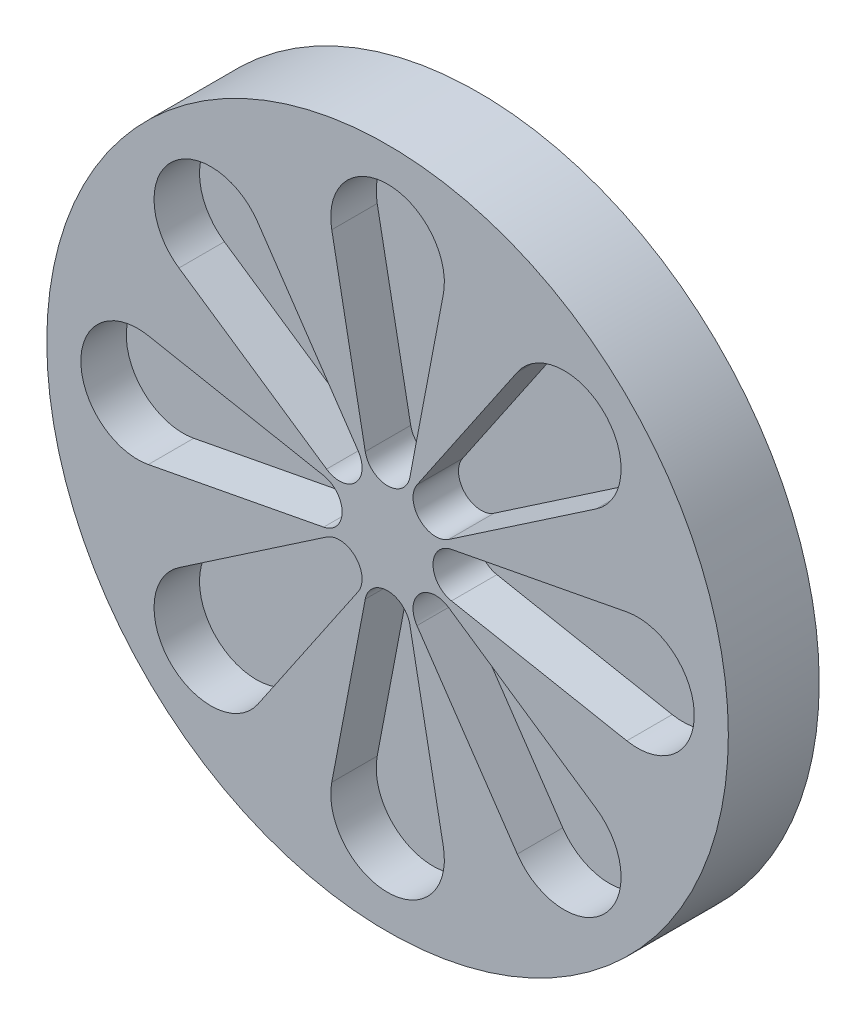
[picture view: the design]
ISO-10303-21;
HEADER;
FILE_DESCRIPTION(('STEP AP214'),'2;1');
FILE_NAME('part.step','',(''),(''),'','','');
FILE_SCHEMA(('AUTOMOTIVE_DESIGN { 1 0 10303 214 1 1 1 1 }'));
ENDSEC;
DATA;
#1=APPLICATION_CONTEXT('core data for automotive mechanical design processes');
#2=APPLICATION_PROTOCOL_DEFINITION('international standard','automotive_design',2000,#1);
#3=PRODUCT_CONTEXT('',#1,'mechanical');
#4=PRODUCT('Part','Part','',(#3));
#5=PRODUCT_RELATED_PRODUCT_CATEGORY('part','',(#4));
#6=PRODUCT_DEFINITION_FORMATION('','',#4);
#7=PRODUCT_DEFINITION_CONTEXT('part definition',#1,'design');
#8=PRODUCT_DEFINITION('design','',#6,#7);
#9=PRODUCT_DEFINITION_SHAPE('','',#8);
#10=(LENGTH_UNIT() NAMED_UNIT(*) SI_UNIT(.MILLI.,.METRE.));
#11=(NAMED_UNIT(*) PLANE_ANGLE_UNIT() SI_UNIT($,.RADIAN.));
#12=(NAMED_UNIT(*) SI_UNIT($,.STERADIAN.) SOLID_ANGLE_UNIT());
#13=UNCERTAINTY_MEASURE_WITH_UNIT(LENGTH_MEASURE(1.E-05),#10,'distance_accuracy_value','');
#14=(GEOMETRIC_REPRESENTATION_CONTEXT(3) GLOBAL_UNCERTAINTY_ASSIGNED_CONTEXT((#13)) GLOBAL_UNIT_ASSIGNED_CONTEXT((#10,
#11,#12)) REPRESENTATION_CONTEXT('',''));
#15=CARTESIAN_POINT('',(0.,0.,0.));
#16=DIRECTION('',(0.,0.,1.));
#17=DIRECTION('',(1.,0.,0.));
#18=AXIS2_PLACEMENT_3D('',#15,#16,#17);
#19=CARTESIAN_POINT('',(0.,0.,40.));
#20=DIRECTION('',(0.,0.,-1.));
#21=DIRECTION('',(-1.,0.,0.));
#22=AXIS2_PLACEMENT_3D('',#19,#20,#21);
#23=CYLINDRICAL_SURFACE('',#22,150.);
#24=CARTESIAN_POINT('',(0.,0.,40.));
#25=DIRECTION('',(0.,0.,1.));
#26=DIRECTION('',(1.,0.,0.));
#27=AXIS2_PLACEMENT_3D('',#24,#25,#26);
#28=CIRCLE('',#27,150.);
#29=CARTESIAN_POINT('',(150.,0.,40.));
#30=VERTEX_POINT('',#29);
#31=EDGE_CURVE('E11',#30,#30,#28,.T.);
#32=ORIENTED_EDGE('',*,*,#31,.F.);
#33=EDGE_LOOP('',(#32));
#34=FACE_BOUND('',#33,.T.);
#35=CARTESIAN_POINT('',(0.,0.,0.));
#36=DIRECTION('',(0.,0.,1.));
#37=DIRECTION('',(1.,0.,0.));
#38=AXIS2_PLACEMENT_3D('',#35,#36,#37);
#39=CIRCLE('',#38,150.);
#40=CARTESIAN_POINT('',(150.,0.,0.));
#41=VERTEX_POINT('',#40);
#42=EDGE_CURVE('E358',#41,#41,#39,.T.);
#43=ORIENTED_EDGE('',*,*,#42,.T.);
#44=EDGE_LOOP('',(#43));
#45=FACE_BOUND('',#44,.T.);
#46=ADVANCED_FACE('F351',(#34,#45),#23,.T.);
#47=CARTESIAN_POINT('',(0.,0.,40.));
#48=DIRECTION('',(0.,0.,1.));
#49=DIRECTION('',(1.,0.,0.));
#50=AXIS2_PLACEMENT_3D('',#47,#48,#49);
#51=PLANE('',#50);
#52=CARTESIAN_POINT('',(77.7817459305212,-77.7817459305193,40.));
#53=DIRECTION('',(0.,0.,1.));
#54=DIRECTION('',(0.707106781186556,-0.707106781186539,0.));
#55=AXIS2_PLACEMENT_3D('',#52,#53,#54);
#56=CIRCLE('',#55,25.);
#57=CARTESIAN_POINT('',(57.1030338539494,-91.8313319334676,40.));
#58=VERTEX_POINT('',#57);
#59=CARTESIAN_POINT('',(91.831331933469,-57.1030338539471,40.));
#60=VERTEX_POINT('',#59);
#61=EDGE_CURVE('E365',#58,#60,#56,.T.);
#62=ORIENTED_EDGE('',*,*,#61,.F.);
#63=DIRECTION('',(0.561983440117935,-0.827148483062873,0.));
#64=VECTOR('',#63,1.);
#65=CARTESIAN_POINT('',(12.941718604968,-26.8330378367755,40.));
#66=LINE('',#65,#64);
#67=CARTESIAN_POINT('',(12.941718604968,-26.8330378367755,40.));
#68=VERTEX_POINT('',#67);
#69=EDGE_CURVE('E581',#68,#58,#66,.T.);
#70=ORIENTED_EDGE('',*,*,#69,.F.);
#71=CARTESIAN_POINT('',(21.2132034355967,-21.2132034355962,40.));
#72=DIRECTION('',(0.,0.,1.));
#73=DIRECTION('',(0.707106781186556,-0.707106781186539,0.));
#74=AXIS2_PLACEMENT_3D('',#71,#72,#73);
#75=CIRCLE('',#74,10.);
#76=CARTESIAN_POINT('',(26.8330378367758,-12.9417186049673,40.));
#77=VERTEX_POINT('',#76);
#78=EDGE_CURVE('E563',#77,#68,#75,.T.);
#79=ORIENTED_EDGE('',*,*,#78,.F.);
#80=DIRECTION('',(-0.827148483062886,0.561983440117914,0.));
#81=VECTOR('',#80,1.);
#82=CARTESIAN_POINT('',(26.8330378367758,-12.9417186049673,40.));
#83=LINE('',#82,#81);
#84=EDGE_CURVE('E574',#60,#77,#83,.T.);
#85=ORIENTED_EDGE('',*,*,#84,.F.);
#86=EDGE_LOOP('',(#62,#70,#79,#85));
#87=FACE_BOUND('',#86,.T.);
#88=CARTESIAN_POINT('',(1.1521895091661E-12,-110.,40.));
#89=DIRECTION('',(0.,0.,1.));
#90=DIRECTION('',(0.,-1.,0.));
#91=AXIS2_PLACEMENT_3D('',#88,#89,#90);
#92=CIRCLE('',#91,25.);
#93=CARTESIAN_POINT('',(-24.5566150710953,-105.3125,40.));
#94=VERTEX_POINT('',#93);
#95=CARTESIAN_POINT('',(24.5566150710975,-105.3125,40.));
#96=VERTEX_POINT('',#95);
#97=EDGE_CURVE('E373',#94,#96,#92,.T.);
#98=ORIENTED_EDGE('',*,*,#97,.F.);
#99=DIRECTION('',(-0.18749999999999,-0.982264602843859,0.));
#100=VECTOR('',#99,1.);
#101=CARTESIAN_POINT('',(-9.82264602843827,-28.1250000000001,40.));
#102=LINE('',#101,#100);
#103=CARTESIAN_POINT('',(-9.82264602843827,-28.1250000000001,40.));
#104=VERTEX_POINT('',#103);
#105=EDGE_CURVE('E606',#104,#94,#102,.T.);
#106=ORIENTED_EDGE('',*,*,#105,.F.);
#107=CARTESIAN_POINT('',(3.14233502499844E-13,-30.,40.));
#108=DIRECTION('',(0.,0.,1.));
#109=DIRECTION('',(0.,-1.,0.));
#110=AXIS2_PLACEMENT_3D('',#107,#108,#109);
#111=CIRCLE('',#110,10.);
#112=CARTESIAN_POINT('',(9.82264602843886,-28.1249999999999,40.));
#113=VERTEX_POINT('',#112);
#114=EDGE_CURVE('E603',#113,#104,#111,.T.);
#115=ORIENTED_EDGE('',*,*,#114,.F.);
#116=DIRECTION('',(-0.18750000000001,0.982264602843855,0.));
#117=VECTOR('',#116,1.);
#118=CARTESIAN_POINT('',(9.82264602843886,-28.1249999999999,40.));
#119=LINE('',#118,#117);
#120=EDGE_CURVE('E600',#96,#113,#119,.T.);
#121=ORIENTED_EDGE('',*,*,#120,.F.);
#122=EDGE_LOOP('',(#98,#106,#115,#121));
#123=FACE_BOUND('',#122,.T.);
#124=CARTESIAN_POINT('',(-77.7817459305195,-77.7817459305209,40.));
#125=DIRECTION('',(0.,0.,1.));
#126=DIRECTION('',(-0.707106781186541,-0.707106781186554,0.));
#127=AXIS2_PLACEMENT_3D('',#124,#125,#126);
#128=CIRCLE('',#127,25.);
#129=CARTESIAN_POINT('',(-91.8313319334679,-57.103033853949,40.));
#130=VERTEX_POINT('',#129);
#131=CARTESIAN_POINT('',(-57.1030338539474,-91.8313319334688,40.));
#132=VERTEX_POINT('',#131);
#133=EDGE_CURVE('E624',#130,#132,#128,.T.);
#134=ORIENTED_EDGE('',*,*,#133,.F.);
#135=DIRECTION('',(-0.827148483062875,-0.561983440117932,0.));
#136=VECTOR('',#135,1.);
#137=CARTESIAN_POINT('',(-26.8330378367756,-12.9417186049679,40.));
#138=LINE('',#137,#136);
#139=CARTESIAN_POINT('',(-26.8330378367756,-12.9417186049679,40.));
#140=VERTEX_POINT('',#139);
#141=EDGE_CURVE('E637',#140,#130,#138,.T.);
#142=ORIENTED_EDGE('',*,*,#141,.F.);
#143=CARTESIAN_POINT('',(-21.2132034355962,-21.2132034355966,40.));
#144=DIRECTION('',(0.,0.,1.));
#145=DIRECTION('',(-0.707106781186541,-0.707106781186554,0.));
#146=AXIS2_PLACEMENT_3D('',#143,#144,#145);
#147=CIRCLE('',#146,10.);
#148=CARTESIAN_POINT('',(-12.9417186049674,-26.8330378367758,40.));
#149=VERTEX_POINT('',#148);
#150=EDGE_CURVE('E634',#149,#140,#147,.T.);
#151=ORIENTED_EDGE('',*,*,#150,.F.);
#152=DIRECTION('',(0.561983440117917,0.827148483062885,0.));
#153=VECTOR('',#152,1.);
#154=CARTESIAN_POINT('',(-12.9417186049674,-26.8330378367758,40.));
#155=LINE('',#154,#153);
#156=EDGE_CURVE('E631',#132,#149,#155,.T.);
#157=ORIENTED_EDGE('',*,*,#156,.F.);
#158=EDGE_LOOP('',(#134,#142,#151,#157));
#159=FACE_BOUND('',#158,.T.);
#160=CARTESIAN_POINT('',(-110.,-7.68126339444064E-13,40.));
#161=DIRECTION('',(0.,0.,1.));
#162=DIRECTION('',(-1.,0.,0.));
#163=AXIS2_PLACEMENT_3D('',#160,#161,#162);
#164=CIRCLE('',#163,25.);
#165=CARTESIAN_POINT('',(-105.3125,24.5566150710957,40.));
#166=VERTEX_POINT('',#165);
#167=CARTESIAN_POINT('',(-105.3125,-24.5566150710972,40.));
#168=VERTEX_POINT('',#167);
#169=EDGE_CURVE('E655',#166,#168,#164,.T.);
#170=ORIENTED_EDGE('',*,*,#169,.F.);
#171=DIRECTION('',(-0.982264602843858,0.187499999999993,0.));
#172=VECTOR('',#171,1.);
#173=CARTESIAN_POINT('',(-28.1250000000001,9.82264602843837,40.));
#174=LINE('',#173,#172);
#175=CARTESIAN_POINT('',(-28.1250000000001,9.82264602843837,40.));
#176=VERTEX_POINT('',#175);
#177=EDGE_CURVE('E669',#176,#166,#174,.T.);
#178=ORIENTED_EDGE('',*,*,#177,.F.);
#179=CARTESIAN_POINT('',(-30.,-2.09489001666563E-13,40.));
#180=DIRECTION('',(0.,0.,1.));
#181=DIRECTION('',(-1.,0.,0.));
#182=AXIS2_PLACEMENT_3D('',#179,#180,#181);
#183=CIRCLE('',#182,10.);
#184=CARTESIAN_POINT('',(-28.1249999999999,-9.82264602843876,40.));
#185=VERTEX_POINT('',#184);
#186=EDGE_CURVE('E666',#185,#176,#183,.T.);
#187=ORIENTED_EDGE('',*,*,#186,.F.);
#188=DIRECTION('',(0.982264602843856,0.187500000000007,0.));
#189=VECTOR('',#188,1.);
#190=CARTESIAN_POINT('',(-28.1249999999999,-9.82264602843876,40.));
#191=LINE('',#190,#189);
#192=EDGE_CURVE('E663',#168,#185,#191,.T.);
#193=ORIENTED_EDGE('',*,*,#192,.F.);
#194=EDGE_LOOP('',(#170,#178,#187,#193));
#195=FACE_BOUND('',#194,.T.);
#196=CARTESIAN_POINT('',(-77.7817459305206,77.7817459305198,40.));
#197=DIRECTION('',(0.,0.,1.));
#198=DIRECTION('',(-0.707106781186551,0.707106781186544,0.));
#199=AXIS2_PLACEMENT_3D('',#196,#197,#198);
#200=CIRCLE('',#199,25.);
#201=CARTESIAN_POINT('',(-57.1030338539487,91.831331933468,40.));
#202=VERTEX_POINT('',#201);
#203=CARTESIAN_POINT('',(-91.8313319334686,57.1030338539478,40.));
#204=VERTEX_POINT('',#203);
#205=EDGE_CURVE('E687',#202,#204,#200,.T.);
#206=ORIENTED_EDGE('',*,*,#205,.F.);
#207=DIRECTION('',(-0.561983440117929,0.827148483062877,0.));
#208=VECTOR('',#207,1.);
#209=CARTESIAN_POINT('',(-12.9417186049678,26.8330378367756,40.));
#210=LINE('',#209,#208);
#211=CARTESIAN_POINT('',(-12.9417186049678,26.8330378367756,40.));
#212=VERTEX_POINT('',#211);
#213=EDGE_CURVE('E701',#212,#202,#210,.T.);
#214=ORIENTED_EDGE('',*,*,#213,.F.);
#215=CARTESIAN_POINT('',(-21.2132034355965,21.2132034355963,40.));
#216=DIRECTION('',(0.,0.,1.));
#217=DIRECTION('',(-0.707106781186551,0.707106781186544,0.));
#218=AXIS2_PLACEMENT_3D('',#215,#216,#217);
#219=CIRCLE('',#218,10.);
#220=CARTESIAN_POINT('',(-26.8330378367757,12.9417186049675,40.));
#221=VERTEX_POINT('',#220);
#222=EDGE_CURVE('E698',#221,#212,#219,.T.);
#223=ORIENTED_EDGE('',*,*,#222,.F.);
#224=DIRECTION('',(0.827148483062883,-0.56198344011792,0.));
#225=VECTOR('',#224,1.);
#226=CARTESIAN_POINT('',(-26.8330378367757,12.9417186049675,40.));
#227=LINE('',#226,#225);
#228=EDGE_CURVE('E695',#204,#221,#227,.T.);
#229=ORIENTED_EDGE('',*,*,#228,.F.);
#230=EDGE_LOOP('',(#206,#214,#223,#229));
#231=FACE_BOUND('',#230,.T.);
#232=CARTESIAN_POINT('',(-3.84063169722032E-13,110.,40.));
#233=DIRECTION('',(0.,0.,1.));
#234=DIRECTION('',(0.,1.,0.));
#235=AXIS2_PLACEMENT_3D('',#232,#233,#234);
#236=CIRCLE('',#235,25.);
#237=CARTESIAN_POINT('',(24.556615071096,105.3125,40.));
#238=VERTEX_POINT('',#237);
#239=CARTESIAN_POINT('',(-24.5566150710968,105.3125,40.));
#240=VERTEX_POINT('',#239);
#241=EDGE_CURVE('E719',#238,#240,#236,.T.);
#242=ORIENTED_EDGE('',*,*,#241,.F.);
#243=DIRECTION('',(0.187499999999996,0.982264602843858,0.));
#244=VECTOR('',#243,1.);
#245=CARTESIAN_POINT('',(9.82264602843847,28.125,40.));
#246=LINE('',#245,#244);
#247=CARTESIAN_POINT('',(9.82264602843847,28.125,40.));
#248=VERTEX_POINT('',#247);
#249=EDGE_CURVE('E733',#248,#238,#246,.T.);
#250=ORIENTED_EDGE('',*,*,#249,.F.);
#251=CARTESIAN_POINT('',(-1.04744500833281E-13,30.,40.));
#252=DIRECTION('',(0.,0.,1.));
#253=DIRECTION('',(0.,1.,0.));
#254=AXIS2_PLACEMENT_3D('',#251,#252,#253);
#255=CIRCLE('',#254,10.);
#256=CARTESIAN_POINT('',(-9.82264602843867,28.125,40.));
#257=VERTEX_POINT('',#256);
#258=EDGE_CURVE('E730',#257,#248,#255,.T.);
#259=ORIENTED_EDGE('',*,*,#258,.F.);
#260=DIRECTION('',(0.187500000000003,-0.982264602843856,0.));
#261=VECTOR('',#260,1.);
#262=CARTESIAN_POINT('',(-9.82264602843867,28.125,40.));
#263=LINE('',#262,#261);
#264=EDGE_CURVE('E727',#240,#257,#263,.T.);
#265=ORIENTED_EDGE('',*,*,#264,.F.);
#266=EDGE_LOOP('',(#242,#250,#259,#265));
#267=FACE_BOUND('',#266,.T.);
#268=CARTESIAN_POINT('',(77.7817459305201,77.7817459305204,40.));
#269=DIRECTION('',(0.,0.,1.));
#270=DIRECTION('',(0.707106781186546,0.707106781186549,0.));
#271=AXIS2_PLACEMENT_3D('',#268,#269,#270);
#272=CIRCLE('',#271,25.);
#273=CARTESIAN_POINT('',(91.8313319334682,57.1030338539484,40.));
#274=VERTEX_POINT('',#273);
#275=CARTESIAN_POINT('',(57.1030338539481,91.8313319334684,40.));
#276=VERTEX_POINT('',#275);
#277=EDGE_CURVE('E751',#274,#276,#272,.T.);
#278=ORIENTED_EDGE('',*,*,#277,.F.);
#279=DIRECTION('',(0.827148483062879,0.561983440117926,0.));
#280=VECTOR('',#279,1.);
#281=CARTESIAN_POINT('',(26.8330378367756,12.9417186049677,40.));
#282=LINE('',#281,#280);
#283=CARTESIAN_POINT('',(26.8330378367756,12.9417186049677,40.));
#284=VERTEX_POINT('',#283);
#285=EDGE_CURVE('E765',#284,#274,#282,.T.);
#286=ORIENTED_EDGE('',*,*,#285,.F.);
#287=CARTESIAN_POINT('',(21.2132034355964,21.2132034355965,40.));
#288=DIRECTION('',(0.,0.,1.));
#289=DIRECTION('',(0.707106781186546,0.707106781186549,0.));
#290=AXIS2_PLACEMENT_3D('',#287,#288,#289);
#291=CIRCLE('',#290,10.);
#292=CARTESIAN_POINT('',(12.9417186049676,26.8330378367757,40.));
#293=VERTEX_POINT('',#292);
#294=EDGE_CURVE('E762',#293,#284,#291,.T.);
#295=ORIENTED_EDGE('',*,*,#294,.F.);
#296=DIRECTION('',(-0.561983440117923,-0.827148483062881,0.));
#297=VECTOR('',#296,1.);
#298=CARTESIAN_POINT('',(12.9417186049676,26.8330378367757,40.));
#299=LINE('',#298,#297);
#300=EDGE_CURVE('E759',#276,#293,#299,.T.);
#301=ORIENTED_EDGE('',*,*,#300,.F.);
#302=EDGE_LOOP('',(#278,#286,#295,#301));
#303=FACE_BOUND('',#302,.T.);
#304=CARTESIAN_POINT('',(110.,0.,40.));
#305=DIRECTION('',(0.,0.,1.));
#306=DIRECTION('',(1.,0.,0.));
#307=AXIS2_PLACEMENT_3D('',#304,#305,#306);
#308=CIRCLE('',#307,25.);
#309=CARTESIAN_POINT('',(105.3125,-24.5566150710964,40.));
#310=VERTEX_POINT('',#309);
#311=CARTESIAN_POINT('',(105.3125,24.5566150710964,40.));
#312=VERTEX_POINT('',#311);
#313=EDGE_CURVE('E783',#310,#312,#308,.T.);
#314=ORIENTED_EDGE('',*,*,#313,.F.);
#315=DIRECTION('',(0.982264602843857,-0.1875,0.));
#316=VECTOR('',#315,1.);
#317=CARTESIAN_POINT('',(28.125,-9.82264602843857,40.));
#318=LINE('',#317,#316);
#319=CARTESIAN_POINT('',(28.125,-9.82264602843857,40.));
#320=VERTEX_POINT('',#319);
#321=EDGE_CURVE('E797',#320,#310,#318,.T.);
#322=ORIENTED_EDGE('',*,*,#321,.F.);
#323=CARTESIAN_POINT('',(30.,0.,40.));
#324=DIRECTION('',(0.,0.,1.));
#325=DIRECTION('',(1.,0.,0.));
#326=AXIS2_PLACEMENT_3D('',#323,#324,#325);
#327=CIRCLE('',#326,10.);
#328=CARTESIAN_POINT('',(28.125,9.82264602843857,40.));
#329=VERTEX_POINT('',#328);
#330=EDGE_CURVE('E794',#329,#320,#327,.T.);
#331=ORIENTED_EDGE('',*,*,#330,.F.);
#332=DIRECTION('',(-0.982264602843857,-0.1875,0.));
#333=VECTOR('',#332,1.);
#334=CARTESIAN_POINT('',(28.125,9.82264602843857,40.));
#335=LINE('',#334,#333);
#336=EDGE_CURVE('E791',#312,#329,#335,.T.);
#337=ORIENTED_EDGE('',*,*,#336,.F.);
#338=EDGE_LOOP('',(#314,#322,#331,#337));
#339=FACE_BOUND('',#338,.T.);
#340=ORIENTED_EDGE('',*,*,#31,.T.);
#341=EDGE_LOOP('',(#340));
#342=FACE_BOUND('',#341,.T.);
#343=ADVANCED_FACE('F578',(#87,#123,#159,#195,#231,#267,#303,#339,#342),#51,.T.);
#344=CARTESIAN_POINT('',(0.,0.,0.));
#345=DIRECTION('',(0.,0.,1.));
#346=DIRECTION('',(1.,0.,0.));
#347=AXIS2_PLACEMENT_3D('',#344,#345,#346);
#348=PLANE('',#347);
#349=ORIENTED_EDGE('',*,*,#42,.F.);
#350=EDGE_LOOP('',(#349));
#351=FACE_BOUND('',#350,.T.);
#352=ADVANCED_FACE('F824',(#351),#348,.F.);
#353=CARTESIAN_POINT('',(110.,0.,20.));
#354=DIRECTION('',(0.,0.,1.));
#355=DIRECTION('',(1.,0.,0.));
#356=AXIS2_PLACEMENT_3D('',#353,#354,#355);
#357=CYLINDRICAL_SURFACE('',#356,25.);
#358=ORIENTED_EDGE('',*,*,#313,.T.);
#359=DIRECTION('',(0.,0.,1.));
#360=VECTOR('',#359,1.);
#361=CARTESIAN_POINT('',(105.3125,24.5566150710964,20.));
#362=LINE('',#361,#360);
#363=CARTESIAN_POINT('',(105.3125,24.5566150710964,20.));
#364=VERTEX_POINT('',#363);
#365=EDGE_CURVE('E812',#364,#312,#362,.T.);
#366=ORIENTED_EDGE('',*,*,#365,.F.);
#367=CARTESIAN_POINT('',(110.,0.,20.));
#368=DIRECTION('',(0.,0.,1.));
#369=DIRECTION('',(1.,0.,0.));
#370=AXIS2_PLACEMENT_3D('',#367,#368,#369);
#371=CIRCLE('',#370,25.);
#372=CARTESIAN_POINT('',(105.3125,-24.5566150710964,20.));
#373=VERTEX_POINT('',#372);
#374=EDGE_CURVE('E800',#373,#364,#371,.T.);
#375=ORIENTED_EDGE('',*,*,#374,.F.);
#376=DIRECTION('',(0.,0.,1.));
#377=VECTOR('',#376,1.);
#378=CARTESIAN_POINT('',(105.3125,-24.5566150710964,20.));
#379=LINE('',#378,#377);
#380=EDGE_CURVE('E813',#373,#310,#379,.T.);
#381=ORIENTED_EDGE('',*,*,#380,.T.);
#382=EDGE_LOOP('',(#358,#366,#375,#381));
#383=FACE_BOUND('',#382,.T.);
#384=ADVANCED_FACE('F826',(#383),#357,.F.);
#385=CARTESIAN_POINT('',(28.125,-9.82264602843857,20.));
#386=DIRECTION('',(-0.1875,-0.982264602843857,0.));
#387=DIRECTION('',(0.982264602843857,-0.1875,0.));
#388=AXIS2_PLACEMENT_3D('',#385,#386,#387);
#389=PLANE('',#388);
#390=ORIENTED_EDGE('',*,*,#321,.T.);
#391=ORIENTED_EDGE('',*,*,#380,.F.);
#392=DIRECTION('',(0.982264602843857,-0.1875,0.));
#393=VECTOR('',#392,1.);
#394=CARTESIAN_POINT('',(28.125,-9.82264602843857,20.));
#395=LINE('',#394,#393);
#396=CARTESIAN_POINT('',(28.125,-9.82264602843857,20.));
#397=VERTEX_POINT('',#396);
#398=EDGE_CURVE('E809',#397,#373,#395,.T.);
#399=ORIENTED_EDGE('',*,*,#398,.F.);
#400=DIRECTION('',(0.,0.,1.));
#401=VECTOR('',#400,1.);
#402=CARTESIAN_POINT('',(28.125,-9.82264602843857,20.));
#403=LINE('',#402,#401);
#404=EDGE_CURVE('E815',#397,#320,#403,.T.);
#405=ORIENTED_EDGE('',*,*,#404,.T.);
#406=EDGE_LOOP('',(#390,#391,#399,#405));
#407=FACE_BOUND('',#406,.T.);
#408=ADVANCED_FACE('F832',(#407),#389,.F.);
#409=CARTESIAN_POINT('',(30.,0.,20.));
#410=DIRECTION('',(0.,0.,1.));
#411=DIRECTION('',(1.,0.,0.));
#412=AXIS2_PLACEMENT_3D('',#409,#410,#411);
#413=CYLINDRICAL_SURFACE('',#412,10.);
#414=ORIENTED_EDGE('',*,*,#330,.T.);
#415=ORIENTED_EDGE('',*,*,#404,.F.);
#416=CARTESIAN_POINT('',(30.,0.,20.));
#417=DIRECTION('',(0.,0.,1.));
#418=DIRECTION('',(1.,0.,0.));
#419=AXIS2_PLACEMENT_3D('',#416,#417,#418);
#420=CIRCLE('',#419,10.);
#421=CARTESIAN_POINT('',(28.125,9.82264602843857,20.));
#422=VERTEX_POINT('',#421);
#423=EDGE_CURVE('E806',#422,#397,#420,.T.);
#424=ORIENTED_EDGE('',*,*,#423,.F.);
#425=DIRECTION('',(0.,0.,1.));
#426=VECTOR('',#425,1.);
#427=CARTESIAN_POINT('',(28.125,9.82264602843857,20.));
#428=LINE('',#427,#426);
#429=EDGE_CURVE('E817',#422,#329,#428,.T.);
#430=ORIENTED_EDGE('',*,*,#429,.T.);
#431=EDGE_LOOP('',(#414,#415,#424,#430));
#432=FACE_BOUND('',#431,.T.);
#433=ADVANCED_FACE('F860',(#432),#413,.F.);
#434=CARTESIAN_POINT('',(28.125,9.82264602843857,20.));
#435=DIRECTION('',(-0.1875,0.982264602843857,0.));
#436=DIRECTION('',(-0.982264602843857,-0.1875,0.));
#437=AXIS2_PLACEMENT_3D('',#434,#435,#436);
#438=PLANE('',#437);
#439=ORIENTED_EDGE('',*,*,#336,.T.);
#440=ORIENTED_EDGE('',*,*,#429,.F.);
#441=DIRECTION('',(-0.982264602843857,-0.1875,0.));
#442=VECTOR('',#441,1.);
#443=CARTESIAN_POINT('',(28.125,9.82264602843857,20.));
#444=LINE('',#443,#442);
#445=EDGE_CURVE('E803',#364,#422,#444,.T.);
#446=ORIENTED_EDGE('',*,*,#445,.F.);
#447=ORIENTED_EDGE('',*,*,#365,.T.);
#448=EDGE_LOOP('',(#439,#440,#446,#447));
#449=FACE_BOUND('',#448,.T.);
#450=ADVANCED_FACE('F868',(#449),#438,.F.);
#451=CARTESIAN_POINT('',(110.,0.,20.));
#452=DIRECTION('',(0.,0.,1.));
#453=DIRECTION('',(1.,0.,0.));
#454=AXIS2_PLACEMENT_3D('',#451,#452,#453);
#455=PLANE('',#454);
#456=ORIENTED_EDGE('',*,*,#374,.T.);
#457=ORIENTED_EDGE('',*,*,#445,.T.);
#458=ORIENTED_EDGE('',*,*,#423,.T.);
#459=ORIENTED_EDGE('',*,*,#398,.T.);
#460=EDGE_LOOP('',(#456,#457,#458,#459));
#461=FACE_BOUND('',#460,.T.);
#462=ADVANCED_FACE('F876',(#461),#455,.T.);
#463=CARTESIAN_POINT('',(77.7817459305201,77.7817459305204,20.));
#464=DIRECTION('',(0.,0.,1.));
#465=DIRECTION('',(1.,0.,0.));
#466=AXIS2_PLACEMENT_3D('',#463,#464,#465);
#467=CYLINDRICAL_SURFACE('',#466,25.);
#468=ORIENTED_EDGE('',*,*,#277,.T.);
#469=DIRECTION('',(0.,0.,1.));
#470=VECTOR('',#469,1.);
#471=CARTESIAN_POINT('',(57.1030338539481,91.8313319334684,20.));
#472=LINE('',#471,#470);
#473=CARTESIAN_POINT('',(57.1030338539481,91.8313319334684,20.));
#474=VERTEX_POINT('',#473);
#475=EDGE_CURVE('E780',#474,#276,#472,.T.);
#476=ORIENTED_EDGE('',*,*,#475,.F.);
#477=CARTESIAN_POINT('',(77.7817459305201,77.7817459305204,20.));
#478=DIRECTION('',(0.,0.,1.));
#479=DIRECTION('',(0.707106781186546,0.707106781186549,0.));
#480=AXIS2_PLACEMENT_3D('',#477,#478,#479);
#481=CIRCLE('',#480,25.);
#482=CARTESIAN_POINT('',(91.8313319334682,57.1030338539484,20.));
#483=VERTEX_POINT('',#482);
#484=EDGE_CURVE('E768',#483,#474,#481,.T.);
#485=ORIENTED_EDGE('',*,*,#484,.F.);
#486=DIRECTION('',(0.,0.,1.));
#487=VECTOR('',#486,1.);
#488=CARTESIAN_POINT('',(91.8313319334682,57.1030338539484,20.));
#489=LINE('',#488,#487);
#490=EDGE_CURVE('E781',#483,#274,#489,.T.);
#491=ORIENTED_EDGE('',*,*,#490,.T.);
#492=EDGE_LOOP('',(#468,#476,#485,#491));
#493=FACE_BOUND('',#492,.T.);
#494=ADVANCED_FACE('F883',(#493),#467,.F.);
#495=CARTESIAN_POINT('',(26.8330378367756,12.9417186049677,20.));
#496=DIRECTION('',(0.561983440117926,-0.827148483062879,0.));
#497=DIRECTION('',(0.827148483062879,0.561983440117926,0.));
#498=AXIS2_PLACEMENT_3D('',#495,#496,#497);
#499=PLANE('',#498);
#500=ORIENTED_EDGE('',*,*,#285,.T.);
#501=ORIENTED_EDGE('',*,*,#490,.F.);
#502=DIRECTION('',(0.827148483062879,0.561983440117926,0.));
#503=VECTOR('',#502,1.);
#504=CARTESIAN_POINT('',(26.8330378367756,12.9417186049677,20.));
#505=LINE('',#504,#503);
#506=CARTESIAN_POINT('',(26.8330378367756,12.9417186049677,20.));
#507=VERTEX_POINT('',#506);
#508=EDGE_CURVE('E777',#507,#483,#505,.T.);
#509=ORIENTED_EDGE('',*,*,#508,.F.);
#510=DIRECTION('',(0.,0.,1.));
#511=VECTOR('',#510,1.);
#512=CARTESIAN_POINT('',(26.8330378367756,12.9417186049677,20.));
#513=LINE('',#512,#511);
#514=EDGE_CURVE('E784',#507,#284,#513,.T.);
#515=ORIENTED_EDGE('',*,*,#514,.T.);
#516=EDGE_LOOP('',(#500,#501,#509,#515));
#517=FACE_BOUND('',#516,.T.);
#518=ADVANCED_FACE('F890',(#517),#499,.F.);
#519=CARTESIAN_POINT('',(21.2132034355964,21.2132034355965,20.));
#520=DIRECTION('',(0.,0.,1.));
#521=DIRECTION('',(1.,0.,0.));
#522=AXIS2_PLACEMENT_3D('',#519,#520,#521);
#523=CYLINDRICAL_SURFACE('',#522,10.);
#524=ORIENTED_EDGE('',*,*,#294,.T.);
#525=ORIENTED_EDGE('',*,*,#514,.F.);
#526=CARTESIAN_POINT('',(21.2132034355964,21.2132034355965,20.));
#527=DIRECTION('',(0.,0.,1.));
#528=DIRECTION('',(0.707106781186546,0.707106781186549,0.));
#529=AXIS2_PLACEMENT_3D('',#526,#527,#528);
#530=CIRCLE('',#529,10.);
#531=CARTESIAN_POINT('',(12.9417186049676,26.8330378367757,20.));
#532=VERTEX_POINT('',#531);
#533=EDGE_CURVE('E774',#532,#507,#530,.T.);
#534=ORIENTED_EDGE('',*,*,#533,.F.);
#535=DIRECTION('',(0.,0.,1.));
#536=VECTOR('',#535,1.);
#537=CARTESIAN_POINT('',(12.9417186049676,26.8330378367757,20.));
#538=LINE('',#537,#536);
#539=EDGE_CURVE('E786',#532,#293,#538,.T.);
#540=ORIENTED_EDGE('',*,*,#539,.T.);
#541=EDGE_LOOP('',(#524,#525,#534,#540));
#542=FACE_BOUND('',#541,.T.);
#543=ADVANCED_FACE('F898',(#542),#523,.F.);
#544=CARTESIAN_POINT('',(12.9417186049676,26.8330378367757,20.));
#545=DIRECTION('',(-0.827148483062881,0.561983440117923,0.));
#546=DIRECTION('',(-0.561983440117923,-0.827148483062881,0.));
#547=AXIS2_PLACEMENT_3D('',#544,#545,#546);
#548=PLANE('',#547);
#549=ORIENTED_EDGE('',*,*,#300,.T.);
#550=ORIENTED_EDGE('',*,*,#539,.F.);
#551=DIRECTION('',(-0.561983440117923,-0.827148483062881,0.));
#552=VECTOR('',#551,1.);
#553=CARTESIAN_POINT('',(12.9417186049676,26.8330378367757,20.));
#554=LINE('',#553,#552);
#555=EDGE_CURVE('E771',#474,#532,#554,.T.);
#556=ORIENTED_EDGE('',*,*,#555,.F.);
#557=ORIENTED_EDGE('',*,*,#475,.T.);
#558=EDGE_LOOP('',(#549,#550,#556,#557));
#559=FACE_BOUND('',#558,.T.);
#560=ADVANCED_FACE('F906',(#559),#548,.F.);
#561=CARTESIAN_POINT('',(77.7817459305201,77.7817459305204,20.));
#562=DIRECTION('',(0.,0.,1.));
#563=DIRECTION('',(0.707106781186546,0.707106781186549,0.));
#564=AXIS2_PLACEMENT_3D('',#561,#562,#563);
#565=PLANE('',#564);
#566=ORIENTED_EDGE('',*,*,#484,.T.);
#567=ORIENTED_EDGE('',*,*,#555,.T.);
#568=ORIENTED_EDGE('',*,*,#533,.T.);
#569=ORIENTED_EDGE('',*,*,#508,.T.);
#570=EDGE_LOOP('',(#566,#567,#568,#569));
#571=FACE_BOUND('',#570,.T.);
#572=ADVANCED_FACE('F914',(#571),#565,.T.);
#573=CARTESIAN_POINT('',(-3.84063169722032E-13,110.,20.));
#574=DIRECTION('',(0.,0.,1.));
#575=DIRECTION('',(1.,0.,0.));
#576=AXIS2_PLACEMENT_3D('',#573,#574,#575);
#577=CYLINDRICAL_SURFACE('',#576,25.);
#578=ORIENTED_EDGE('',*,*,#241,.T.);
#579=DIRECTION('',(0.,0.,1.));
#580=VECTOR('',#579,1.);
#581=CARTESIAN_POINT('',(-24.5566150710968,105.3125,20.));
#582=LINE('',#581,#580);
#583=CARTESIAN_POINT('',(-24.5566150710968,105.3125,20.));
#584=VERTEX_POINT('',#583);
#585=EDGE_CURVE('E748',#584,#240,#582,.T.);
#586=ORIENTED_EDGE('',*,*,#585,.F.);
#587=CARTESIAN_POINT('',(-3.84063169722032E-13,110.,20.));
#588=DIRECTION('',(0.,0.,1.));
#589=DIRECTION('',(0.,1.,0.));
#590=AXIS2_PLACEMENT_3D('',#587,#588,#589);
#591=CIRCLE('',#590,25.);
#592=CARTESIAN_POINT('',(24.556615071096,105.3125,20.));
#593=VERTEX_POINT('',#592);
#594=EDGE_CURVE('E736',#593,#584,#591,.T.);
#595=ORIENTED_EDGE('',*,*,#594,.F.);
#596=DIRECTION('',(0.,0.,1.));
#597=VECTOR('',#596,1.);
#598=CARTESIAN_POINT('',(24.556615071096,105.3125,20.));
#599=LINE('',#598,#597);
#600=EDGE_CURVE('E749',#593,#238,#599,.T.);
#601=ORIENTED_EDGE('',*,*,#600,.T.);
#602=EDGE_LOOP('',(#578,#586,#595,#601));
#603=FACE_BOUND('',#602,.T.);
#604=ADVANCED_FACE('F922',(#603),#577,.F.);
#605=CARTESIAN_POINT('',(9.82264602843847,28.125,20.));
#606=DIRECTION('',(0.982264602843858,-0.187499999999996,0.));
#607=DIRECTION('',(0.187499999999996,0.982264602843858,0.));
#608=AXIS2_PLACEMENT_3D('',#605,#606,#607);
#609=PLANE('',#608);
#610=ORIENTED_EDGE('',*,*,#249,.T.);
#611=ORIENTED_EDGE('',*,*,#600,.F.);
#612=DIRECTION('',(0.187499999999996,0.982264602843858,0.));
#613=VECTOR('',#612,1.);
#614=CARTESIAN_POINT('',(9.82264602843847,28.125,20.));
#615=LINE('',#614,#613);
#616=CARTESIAN_POINT('',(9.82264602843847,28.125,20.));
#617=VERTEX_POINT('',#616);
#618=EDGE_CURVE('E745',#617,#593,#615,.T.);
#619=ORIENTED_EDGE('',*,*,#618,.F.);
#620=DIRECTION('',(0.,0.,1.));
#621=VECTOR('',#620,1.);
#622=CARTESIAN_POINT('',(9.82264602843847,28.125,20.));
#623=LINE('',#622,#621);
#624=EDGE_CURVE('E752',#617,#248,#623,.T.);
#625=ORIENTED_EDGE('',*,*,#624,.T.);
#626=EDGE_LOOP('',(#610,#611,#619,#625));
#627=FACE_BOUND('',#626,.T.);
#628=ADVANCED_FACE('F930',(#627),#609,.F.);
#629=CARTESIAN_POINT('',(-1.04744500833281E-13,30.,20.));
#630=DIRECTION('',(0.,0.,1.));
#631=DIRECTION('',(1.,0.,0.));
#632=AXIS2_PLACEMENT_3D('',#629,#630,#631);
#633=CYLINDRICAL_SURFACE('',#632,10.);
#634=ORIENTED_EDGE('',*,*,#258,.T.);
#635=ORIENTED_EDGE('',*,*,#624,.F.);
#636=CARTESIAN_POINT('',(-1.04744500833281E-13,30.,20.));
#637=DIRECTION('',(0.,0.,1.));
#638=DIRECTION('',(0.,1.,0.));
#639=AXIS2_PLACEMENT_3D('',#636,#637,#638);
#640=CIRCLE('',#639,10.);
#641=CARTESIAN_POINT('',(-9.82264602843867,28.125,20.));
#642=VERTEX_POINT('',#641);
#643=EDGE_CURVE('E742',#642,#617,#640,.T.);
#644=ORIENTED_EDGE('',*,*,#643,.F.);
#645=DIRECTION('',(0.,0.,1.));
#646=VECTOR('',#645,1.);
#647=CARTESIAN_POINT('',(-9.82264602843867,28.125,20.));
#648=LINE('',#647,#646);
#649=EDGE_CURVE('E754',#642,#257,#648,.T.);
#650=ORIENTED_EDGE('',*,*,#649,.T.);
#651=EDGE_LOOP('',(#634,#635,#644,#650));
#652=FACE_BOUND('',#651,.T.);
#653=ADVANCED_FACE('F938',(#652),#633,.F.);
#654=CARTESIAN_POINT('',(-9.82264602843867,28.125,20.));
#655=DIRECTION('',(-0.982264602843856,-0.187500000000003,0.));
#656=DIRECTION('',(0.187500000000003,-0.982264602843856,0.));
#657=AXIS2_PLACEMENT_3D('',#654,#655,#656);
#658=PLANE('',#657);
#659=ORIENTED_EDGE('',*,*,#264,.T.);
#660=ORIENTED_EDGE('',*,*,#649,.F.);
#661=DIRECTION('',(0.187500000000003,-0.982264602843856,0.));
#662=VECTOR('',#661,1.);
#663=CARTESIAN_POINT('',(-9.82264602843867,28.125,20.));
#664=LINE('',#663,#662);
#665=EDGE_CURVE('E739',#584,#642,#664,.T.);
#666=ORIENTED_EDGE('',*,*,#665,.F.);
#667=ORIENTED_EDGE('',*,*,#585,.T.);
#668=EDGE_LOOP('',(#659,#660,#666,#667));
#669=FACE_BOUND('',#668,.T.);
#670=ADVANCED_FACE('F946',(#669),#658,.F.);
#671=CARTESIAN_POINT('',(-3.84063169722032E-13,110.,20.));
#672=DIRECTION('',(0.,0.,1.));
#673=DIRECTION('',(0.,1.,0.));
#674=AXIS2_PLACEMENT_3D('',#671,#672,#673);
#675=PLANE('',#674);
#676=ORIENTED_EDGE('',*,*,#594,.T.);
#677=ORIENTED_EDGE('',*,*,#665,.T.);
#678=ORIENTED_EDGE('',*,*,#643,.T.);
#679=ORIENTED_EDGE('',*,*,#618,.T.);
#680=EDGE_LOOP('',(#676,#677,#678,#679));
#681=FACE_BOUND('',#680,.T.);
#682=ADVANCED_FACE('F954',(#681),#675,.T.);
#683=CARTESIAN_POINT('',(-77.7817459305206,77.7817459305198,20.));
#684=DIRECTION('',(0.,0.,1.));
#685=DIRECTION('',(1.,0.,0.));
#686=AXIS2_PLACEMENT_3D('',#683,#684,#685);
#687=CYLINDRICAL_SURFACE('',#686,25.);
#688=ORIENTED_EDGE('',*,*,#205,.T.);
#689=DIRECTION('',(0.,0.,1.));
#690=VECTOR('',#689,1.);
#691=CARTESIAN_POINT('',(-91.8313319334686,57.1030338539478,20.));
#692=LINE('',#691,#690);
#693=CARTESIAN_POINT('',(-91.8313319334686,57.1030338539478,20.));
#694=VERTEX_POINT('',#693);
#695=EDGE_CURVE('E716',#694,#204,#692,.T.);
#696=ORIENTED_EDGE('',*,*,#695,.F.);
#697=CARTESIAN_POINT('',(-77.7817459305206,77.7817459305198,20.));
#698=DIRECTION('',(0.,0.,1.));
#699=DIRECTION('',(-0.707106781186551,0.707106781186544,0.));
#700=AXIS2_PLACEMENT_3D('',#697,#698,#699);
#701=CIRCLE('',#700,25.);
#702=CARTESIAN_POINT('',(-57.1030338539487,91.831331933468,20.));
#703=VERTEX_POINT('',#702);
#704=EDGE_CURVE('E704',#703,#694,#701,.T.);
#705=ORIENTED_EDGE('',*,*,#704,.F.);
#706=DIRECTION('',(0.,0.,1.));
#707=VECTOR('',#706,1.);
#708=CARTESIAN_POINT('',(-57.1030338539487,91.831331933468,20.));
#709=LINE('',#708,#707);
#710=EDGE_CURVE('E717',#703,#202,#709,.T.);
#711=ORIENTED_EDGE('',*,*,#710,.T.);
#712=EDGE_LOOP('',(#688,#696,#705,#711));
#713=FACE_BOUND('',#712,.T.);
#714=ADVANCED_FACE('F962',(#713),#687,.F.);
#715=CARTESIAN_POINT('',(-12.9417186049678,26.8330378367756,20.));
#716=DIRECTION('',(0.827148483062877,0.561983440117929,0.));
#717=DIRECTION('',(-0.561983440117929,0.827148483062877,0.));
#718=AXIS2_PLACEMENT_3D('',#715,#716,#717);
#719=PLANE('',#718);
#720=ORIENTED_EDGE('',*,*,#213,.T.);
#721=ORIENTED_EDGE('',*,*,#710,.F.);
#722=DIRECTION('',(-0.561983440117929,0.827148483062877,0.));
#723=VECTOR('',#722,1.);
#724=CARTESIAN_POINT('',(-12.9417186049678,26.8330378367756,20.));
#725=LINE('',#724,#723);
#726=CARTESIAN_POINT('',(-12.9417186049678,26.8330378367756,20.));
#727=VERTEX_POINT('',#726);
#728=EDGE_CURVE('E713',#727,#703,#725,.T.);
#729=ORIENTED_EDGE('',*,*,#728,.F.);
#730=DIRECTION('',(0.,0.,1.));
#731=VECTOR('',#730,1.);
#732=CARTESIAN_POINT('',(-12.9417186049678,26.8330378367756,20.));
#733=LINE('',#732,#731);
#734=EDGE_CURVE('E720',#727,#212,#733,.T.);
#735=ORIENTED_EDGE('',*,*,#734,.T.);
#736=EDGE_LOOP('',(#720,#721,#729,#735));
#737=FACE_BOUND('',#736,.T.);
#738=ADVANCED_FACE('F970',(#737),#719,.F.);
#739=CARTESIAN_POINT('',(-21.2132034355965,21.2132034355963,20.));
#740=DIRECTION('',(0.,0.,1.));
#741=DIRECTION('',(1.,0.,0.));
#742=AXIS2_PLACEMENT_3D('',#739,#740,#741);
#743=CYLINDRICAL_SURFACE('',#742,10.);
#744=ORIENTED_EDGE('',*,*,#222,.T.);
#745=ORIENTED_EDGE('',*,*,#734,.F.);
#746=CARTESIAN_POINT('',(-21.2132034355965,21.2132034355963,20.));
#747=DIRECTION('',(0.,0.,1.));
#748=DIRECTION('',(-0.707106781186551,0.707106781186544,0.));
#749=AXIS2_PLACEMENT_3D('',#746,#747,#748);
#750=CIRCLE('',#749,10.);
#751=CARTESIAN_POINT('',(-26.8330378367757,12.9417186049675,20.));
#752=VERTEX_POINT('',#751);
#753=EDGE_CURVE('E710',#752,#727,#750,.T.);
#754=ORIENTED_EDGE('',*,*,#753,.F.);
#755=DIRECTION('',(0.,0.,1.));
#756=VECTOR('',#755,1.);
#757=CARTESIAN_POINT('',(-26.8330378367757,12.9417186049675,20.));
#758=LINE('',#757,#756);
#759=EDGE_CURVE('E722',#752,#221,#758,.T.);
#760=ORIENTED_EDGE('',*,*,#759,.T.);
#761=EDGE_LOOP('',(#744,#745,#754,#760));
#762=FACE_BOUND('',#761,.T.);
#763=ADVANCED_FACE('F978',(#762),#743,.F.);
#764=CARTESIAN_POINT('',(-26.8330378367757,12.9417186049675,20.));
#765=DIRECTION('',(-0.56198344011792,-0.827148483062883,0.));
#766=DIRECTION('',(0.827148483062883,-0.56198344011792,0.));
#767=AXIS2_PLACEMENT_3D('',#764,#765,#766);
#768=PLANE('',#767);
#769=ORIENTED_EDGE('',*,*,#228,.T.);
#770=ORIENTED_EDGE('',*,*,#759,.F.);
#771=DIRECTION('',(0.827148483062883,-0.56198344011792,0.));
#772=VECTOR('',#771,1.);
#773=CARTESIAN_POINT('',(-26.8330378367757,12.9417186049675,20.));
#774=LINE('',#773,#772);
#775=EDGE_CURVE('E707',#694,#752,#774,.T.);
#776=ORIENTED_EDGE('',*,*,#775,.F.);
#777=ORIENTED_EDGE('',*,*,#695,.T.);
#778=EDGE_LOOP('',(#769,#770,#776,#777));
#779=FACE_BOUND('',#778,.T.);
#780=ADVANCED_FACE('F986',(#779),#768,.F.);
#781=CARTESIAN_POINT('',(-77.7817459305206,77.7817459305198,20.));
#782=DIRECTION('',(0.,0.,1.));
#783=DIRECTION('',(-0.707106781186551,0.707106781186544,0.));
#784=AXIS2_PLACEMENT_3D('',#781,#782,#783);
#785=PLANE('',#784);
#786=ORIENTED_EDGE('',*,*,#704,.T.);
#787=ORIENTED_EDGE('',*,*,#775,.T.);
#788=ORIENTED_EDGE('',*,*,#753,.T.);
#789=ORIENTED_EDGE('',*,*,#728,.T.);
#790=EDGE_LOOP('',(#786,#787,#788,#789));
#791=FACE_BOUND('',#790,.T.);
#792=ADVANCED_FACE('F994',(#791),#785,.T.);
#793=CARTESIAN_POINT('',(-110.,-7.68126339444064E-13,20.));
#794=DIRECTION('',(0.,0.,1.));
#795=DIRECTION('',(1.,0.,0.));
#796=AXIS2_PLACEMENT_3D('',#793,#794,#795);
#797=CYLINDRICAL_SURFACE('',#796,25.);
#798=ORIENTED_EDGE('',*,*,#169,.T.);
#799=DIRECTION('',(0.,0.,1.));
#800=VECTOR('',#799,1.);
#801=CARTESIAN_POINT('',(-105.3125,-24.5566150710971,20.));
#802=LINE('',#801,#800);
#803=CARTESIAN_POINT('',(-105.3125,-24.5566150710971,20.));
#804=VERTEX_POINT('',#803);
#805=EDGE_CURVE('E684',#804,#168,#802,.T.);
#806=ORIENTED_EDGE('',*,*,#805,.F.);
#807=CARTESIAN_POINT('',(-110.,-7.68126339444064E-13,20.));
#808=DIRECTION('',(0.,0.,1.));
#809=DIRECTION('',(-1.,0.,0.));
#810=AXIS2_PLACEMENT_3D('',#807,#808,#809);
#811=CIRCLE('',#810,25.);
#812=CARTESIAN_POINT('',(-105.3125,24.5566150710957,20.));
#813=VERTEX_POINT('',#812);
#814=EDGE_CURVE('E672',#813,#804,#811,.T.);
#815=ORIENTED_EDGE('',*,*,#814,.F.);
#816=DIRECTION('',(0.,0.,1.));
#817=VECTOR('',#816,1.);
#818=CARTESIAN_POINT('',(-105.3125,24.5566150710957,20.));
#819=LINE('',#818,#817);
#820=EDGE_CURVE('E685',#813,#166,#819,.T.);
#821=ORIENTED_EDGE('',*,*,#820,.T.);
#822=EDGE_LOOP('',(#798,#806,#815,#821));
#823=FACE_BOUND('',#822,.T.);
#824=ADVANCED_FACE('F1002',(#823),#797,.F.);
#825=CARTESIAN_POINT('',(-28.1250000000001,9.82264602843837,20.));
#826=DIRECTION('',(0.187499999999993,0.982264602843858,0.));
#827=DIRECTION('',(-0.982264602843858,0.187499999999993,0.));
#828=AXIS2_PLACEMENT_3D('',#825,#826,#827);
#829=PLANE('',#828);
#830=ORIENTED_EDGE('',*,*,#177,.T.);
#831=ORIENTED_EDGE('',*,*,#820,.F.);
#832=DIRECTION('',(-0.982264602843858,0.187499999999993,0.));
#833=VECTOR('',#832,1.);
#834=CARTESIAN_POINT('',(-28.1250000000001,9.82264602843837,20.));
#835=LINE('',#834,#833);
#836=CARTESIAN_POINT('',(-28.1250000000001,9.82264602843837,20.));
#837=VERTEX_POINT('',#836);
#838=EDGE_CURVE('E681',#837,#813,#835,.T.);
#839=ORIENTED_EDGE('',*,*,#838,.F.);
#840=DIRECTION('',(0.,0.,1.));
#841=VECTOR('',#840,1.);
#842=CARTESIAN_POINT('',(-28.1250000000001,9.82264602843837,20.));
#843=LINE('',#842,#841);
#844=EDGE_CURVE('E688',#837,#176,#843,.T.);
#845=ORIENTED_EDGE('',*,*,#844,.T.);
#846=EDGE_LOOP('',(#830,#831,#839,#845));
#847=FACE_BOUND('',#846,.T.);
#848=ADVANCED_FACE('F1010',(#847),#829,.F.);
#849=CARTESIAN_POINT('',(-30.,-2.09489001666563E-13,20.));
#850=DIRECTION('',(0.,0.,1.));
#851=DIRECTION('',(1.,0.,0.));
#852=AXIS2_PLACEMENT_3D('',#849,#850,#851);
#853=CYLINDRICAL_SURFACE('',#852,10.);
#854=ORIENTED_EDGE('',*,*,#186,.T.);
#855=ORIENTED_EDGE('',*,*,#844,.F.);
#856=CARTESIAN_POINT('',(-30.,-2.09489001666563E-13,20.));
#857=DIRECTION('',(0.,0.,1.));
#858=DIRECTION('',(-1.,0.,0.));
#859=AXIS2_PLACEMENT_3D('',#856,#857,#858);
#860=CIRCLE('',#859,10.);
#861=CARTESIAN_POINT('',(-28.1249999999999,-9.82264602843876,20.));
#862=VERTEX_POINT('',#861);
#863=EDGE_CURVE('E678',#862,#837,#860,.T.);
#864=ORIENTED_EDGE('',*,*,#863,.F.);
#865=DIRECTION('',(0.,0.,1.));
#866=VECTOR('',#865,1.);
#867=CARTESIAN_POINT('',(-28.1249999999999,-9.82264602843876,20.));
#868=LINE('',#867,#866);
#869=EDGE_CURVE('E690',#862,#185,#868,.T.);
#870=ORIENTED_EDGE('',*,*,#869,.T.);
#871=EDGE_LOOP('',(#854,#855,#864,#870));
#872=FACE_BOUND('',#871,.T.);
#873=ADVANCED_FACE('F1018',(#872),#853,.F.);
#874=CARTESIAN_POINT('',(-28.1249999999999,-9.82264602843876,20.));
#875=DIRECTION('',(0.187500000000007,-0.982264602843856,0.));
#876=DIRECTION('',(0.982264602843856,0.187500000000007,0.));
#877=AXIS2_PLACEMENT_3D('',#874,#875,#876);
#878=PLANE('',#877);
#879=ORIENTED_EDGE('',*,*,#192,.T.);
#880=ORIENTED_EDGE('',*,*,#869,.F.);
#881=DIRECTION('',(0.982264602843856,0.187500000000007,0.));
#882=VECTOR('',#881,1.);
#883=CARTESIAN_POINT('',(-28.1249999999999,-9.82264602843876,20.));
#884=LINE('',#883,#882);
#885=EDGE_CURVE('E675',#804,#862,#884,.T.);
#886=ORIENTED_EDGE('',*,*,#885,.F.);
#887=ORIENTED_EDGE('',*,*,#805,.T.);
#888=EDGE_LOOP('',(#879,#880,#886,#887));
#889=FACE_BOUND('',#888,.T.);
#890=ADVANCED_FACE('F1026',(#889),#878,.F.);
#891=CARTESIAN_POINT('',(-110.,-7.68126339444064E-13,20.));
#892=DIRECTION('',(0.,0.,1.));
#893=DIRECTION('',(-1.,0.,0.));
#894=AXIS2_PLACEMENT_3D('',#891,#892,#893);
#895=PLANE('',#894);
#896=ORIENTED_EDGE('',*,*,#814,.T.);
#897=ORIENTED_EDGE('',*,*,#885,.T.);
#898=ORIENTED_EDGE('',*,*,#863,.T.);
#899=ORIENTED_EDGE('',*,*,#838,.T.);
#900=EDGE_LOOP('',(#896,#897,#898,#899));
#901=FACE_BOUND('',#900,.T.);
#902=ADVANCED_FACE('F1034',(#901),#895,.T.);
#903=CARTESIAN_POINT('',(-77.7817459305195,-77.7817459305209,20.));
#904=DIRECTION('',(0.,0.,1.));
#905=DIRECTION('',(1.,0.,0.));
#906=AXIS2_PLACEMENT_3D('',#903,#904,#905);
#907=CYLINDRICAL_SURFACE('',#906,25.);
#908=ORIENTED_EDGE('',*,*,#133,.T.);
#909=DIRECTION('',(0.,0.,1.));
#910=VECTOR('',#909,1.);
#911=CARTESIAN_POINT('',(-57.1030338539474,-91.8313319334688,20.));
#912=LINE('',#911,#910);
#913=CARTESIAN_POINT('',(-57.1030338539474,-91.8313319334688,20.));
#914=VERTEX_POINT('',#913);
#915=EDGE_CURVE('E652',#914,#132,#912,.T.);
#916=ORIENTED_EDGE('',*,*,#915,.F.);
#917=CARTESIAN_POINT('',(-77.7817459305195,-77.7817459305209,20.));
#918=DIRECTION('',(0.,0.,1.));
#919=DIRECTION('',(-0.707106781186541,-0.707106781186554,0.));
#920=AXIS2_PLACEMENT_3D('',#917,#918,#919);
#921=CIRCLE('',#920,25.);
#922=CARTESIAN_POINT('',(-91.8313319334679,-57.103033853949,20.));
#923=VERTEX_POINT('',#922);
#924=EDGE_CURVE('E640',#923,#914,#921,.T.);
#925=ORIENTED_EDGE('',*,*,#924,.F.);
#926=DIRECTION('',(0.,0.,1.));
#927=VECTOR('',#926,1.);
#928=CARTESIAN_POINT('',(-91.8313319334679,-57.103033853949,20.));
#929=LINE('',#928,#927);
#930=EDGE_CURVE('E653',#923,#130,#929,.T.);
#931=ORIENTED_EDGE('',*,*,#930,.T.);
#932=EDGE_LOOP('',(#908,#916,#925,#931));
#933=FACE_BOUND('',#932,.T.);
#934=ADVANCED_FACE('F1042',(#933),#907,.F.);
#935=CARTESIAN_POINT('',(-26.8330378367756,-12.9417186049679,20.));
#936=DIRECTION('',(-0.561983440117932,0.827148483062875,0.));
#937=DIRECTION('',(-0.827148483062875,-0.561983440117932,0.));
#938=AXIS2_PLACEMENT_3D('',#935,#936,#937);
#939=PLANE('',#938);
#940=ORIENTED_EDGE('',*,*,#141,.T.);
#941=ORIENTED_EDGE('',*,*,#930,.F.);
#942=DIRECTION('',(-0.827148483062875,-0.561983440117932,0.));
#943=VECTOR('',#942,1.);
#944=CARTESIAN_POINT('',(-26.8330378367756,-12.9417186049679,20.));
#945=LINE('',#944,#943);
#946=CARTESIAN_POINT('',(-26.8330378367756,-12.9417186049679,20.));
#947=VERTEX_POINT('',#946);
#948=EDGE_CURVE('E649',#947,#923,#945,.T.);
#949=ORIENTED_EDGE('',*,*,#948,.F.);
#950=DIRECTION('',(0.,0.,1.));
#951=VECTOR('',#950,1.);
#952=CARTESIAN_POINT('',(-26.8330378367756,-12.9417186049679,20.));
#953=LINE('',#952,#951);
#954=EDGE_CURVE('E656',#947,#140,#953,.T.);
#955=ORIENTED_EDGE('',*,*,#954,.T.);
#956=EDGE_LOOP('',(#940,#941,#949,#955));
#957=FACE_BOUND('',#956,.T.);
#958=ADVANCED_FACE('F1050',(#957),#939,.F.);
#959=CARTESIAN_POINT('',(-21.2132034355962,-21.2132034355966,20.));
#960=DIRECTION('',(0.,0.,1.));
#961=DIRECTION('',(1.,0.,0.));
#962=AXIS2_PLACEMENT_3D('',#959,#960,#961);
#963=CYLINDRICAL_SURFACE('',#962,10.);
#964=ORIENTED_EDGE('',*,*,#150,.T.);
#965=ORIENTED_EDGE('',*,*,#954,.F.);
#966=CARTESIAN_POINT('',(-21.2132034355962,-21.2132034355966,20.));
#967=DIRECTION('',(0.,0.,1.));
#968=DIRECTION('',(-0.707106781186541,-0.707106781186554,0.));
#969=AXIS2_PLACEMENT_3D('',#966,#967,#968);
#970=CIRCLE('',#969,10.);
#971=CARTESIAN_POINT('',(-12.9417186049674,-26.8330378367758,20.));
#972=VERTEX_POINT('',#971);
#973=EDGE_CURVE('E646',#972,#947,#970,.T.);
#974=ORIENTED_EDGE('',*,*,#973,.F.);
#975=DIRECTION('',(0.,0.,1.));
#976=VECTOR('',#975,1.);
#977=CARTESIAN_POINT('',(-12.9417186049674,-26.8330378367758,20.));
#978=LINE('',#977,#976);
#979=EDGE_CURVE('E658',#972,#149,#978,.T.);
#980=ORIENTED_EDGE('',*,*,#979,.T.);
#981=EDGE_LOOP('',(#964,#965,#974,#980));
#982=FACE_BOUND('',#981,.T.);
#983=ADVANCED_FACE('F1058',(#982),#963,.F.);
#984=CARTESIAN_POINT('',(-12.9417186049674,-26.8330378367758,20.));
#985=DIRECTION('',(0.827148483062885,-0.561983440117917,0.));
#986=DIRECTION('',(0.561983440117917,0.827148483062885,0.));
#987=AXIS2_PLACEMENT_3D('',#984,#985,#986);
#988=PLANE('',#987);
#989=ORIENTED_EDGE('',*,*,#156,.T.);
#990=ORIENTED_EDGE('',*,*,#979,.F.);
#991=DIRECTION('',(0.561983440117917,0.827148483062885,0.));
#992=VECTOR('',#991,1.);
#993=CARTESIAN_POINT('',(-12.9417186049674,-26.8330378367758,20.));
#994=LINE('',#993,#992);
#995=EDGE_CURVE('E643',#914,#972,#994,.T.);
#996=ORIENTED_EDGE('',*,*,#995,.F.);
#997=ORIENTED_EDGE('',*,*,#915,.T.);
#998=EDGE_LOOP('',(#989,#990,#996,#997));
#999=FACE_BOUND('',#998,.T.);
#1000=ADVANCED_FACE('F1066',(#999),#988,.F.);
#1001=CARTESIAN_POINT('',(-77.7817459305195,-77.7817459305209,20.));
#1002=DIRECTION('',(0.,0.,1.));
#1003=DIRECTION('',(-0.707106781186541,-0.707106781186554,0.));
#1004=AXIS2_PLACEMENT_3D('',#1001,#1002,#1003);
#1005=PLANE('',#1004);
#1006=ORIENTED_EDGE('',*,*,#924,.T.);
#1007=ORIENTED_EDGE('',*,*,#995,.T.);
#1008=ORIENTED_EDGE('',*,*,#973,.T.);
#1009=ORIENTED_EDGE('',*,*,#948,.T.);
#1010=EDGE_LOOP('',(#1006,#1007,#1008,#1009));
#1011=FACE_BOUND('',#1010,.T.);
#1012=ADVANCED_FACE('F1074',(#1011),#1005,.T.);
#1013=CARTESIAN_POINT('',(1.1521895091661E-12,-110.,20.));
#1014=DIRECTION('',(0.,0.,1.));
#1015=DIRECTION('',(1.,0.,0.));
#1016=AXIS2_PLACEMENT_3D('',#1013,#1014,#1015);
#1017=CYLINDRICAL_SURFACE('',#1016,25.);
#1018=ORIENTED_EDGE('',*,*,#97,.T.);
#1019=DIRECTION('',(0.,0.,1.));
#1020=VECTOR('',#1019,1.);
#1021=CARTESIAN_POINT('',(24.5566150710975,-105.3125,20.));
#1022=LINE('',#1021,#1020);
#1023=CARTESIAN_POINT('',(24.5566150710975,-105.3125,20.));
#1024=VERTEX_POINT('',#1023);
#1025=EDGE_CURVE('E621',#1024,#96,#1022,.T.);
#1026=ORIENTED_EDGE('',*,*,#1025,.F.);
#1027=CARTESIAN_POINT('',(1.1521895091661E-12,-110.,20.));
#1028=DIRECTION('',(0.,0.,1.));
#1029=DIRECTION('',(0.,-1.,0.));
#1030=AXIS2_PLACEMENT_3D('',#1027,#1028,#1029);
#1031=CIRCLE('',#1030,25.);
#1032=CARTESIAN_POINT('',(-24.5566150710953,-105.3125,20.));
#1033=VERTEX_POINT('',#1032);
#1034=EDGE_CURVE('E609',#1033,#1024,#1031,.T.);
#1035=ORIENTED_EDGE('',*,*,#1034,.F.);
#1036=DIRECTION('',(0.,0.,1.));
#1037=VECTOR('',#1036,1.);
#1038=CARTESIAN_POINT('',(-24.5566150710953,-105.3125,20.));
#1039=LINE('',#1038,#1037);
#1040=EDGE_CURVE('E622',#1033,#94,#1039,.T.);
#1041=ORIENTED_EDGE('',*,*,#1040,.T.);
#1042=EDGE_LOOP('',(#1018,#1026,#1035,#1041));
#1043=FACE_BOUND('',#1042,.T.);
#1044=ADVANCED_FACE('F1082',(#1043),#1017,.F.);
#1045=CARTESIAN_POINT('',(-9.82264602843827,-28.1250000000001,20.));
#1046=DIRECTION('',(-0.982264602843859,0.18749999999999,0.));
#1047=DIRECTION('',(-0.18749999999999,-0.982264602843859,0.));
#1048=AXIS2_PLACEMENT_3D('',#1045,#1046,#1047);
#1049=PLANE('',#1048);
#1050=ORIENTED_EDGE('',*,*,#105,.T.);
#1051=ORIENTED_EDGE('',*,*,#1040,.F.);
#1052=DIRECTION('',(-0.18749999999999,-0.982264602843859,0.));
#1053=VECTOR('',#1052,1.);
#1054=CARTESIAN_POINT('',(-9.82264602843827,-28.1250000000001,20.));
#1055=LINE('',#1054,#1053);
#1056=CARTESIAN_POINT('',(-9.82264602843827,-28.1250000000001,20.));
#1057=VERTEX_POINT('',#1056);
#1058=EDGE_CURVE('E618',#1057,#1033,#1055,.T.);
#1059=ORIENTED_EDGE('',*,*,#1058,.F.);
#1060=DIRECTION('',(0.,0.,1.));
#1061=VECTOR('',#1060,1.);
#1062=CARTESIAN_POINT('',(-9.82264602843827,-28.1250000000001,20.));
#1063=LINE('',#1062,#1061);
#1064=EDGE_CURVE('E625',#1057,#104,#1063,.T.);
#1065=ORIENTED_EDGE('',*,*,#1064,.T.);
#1066=EDGE_LOOP('',(#1050,#1051,#1059,#1065));
#1067=FACE_BOUND('',#1066,.T.);
#1068=ADVANCED_FACE('F1090',(#1067),#1049,.F.);
#1069=CARTESIAN_POINT('',(3.14233502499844E-13,-30.,20.));
#1070=DIRECTION('',(0.,0.,1.));
#1071=DIRECTION('',(1.,0.,0.));
#1072=AXIS2_PLACEMENT_3D('',#1069,#1070,#1071);
#1073=CYLINDRICAL_SURFACE('',#1072,10.);
#1074=ORIENTED_EDGE('',*,*,#114,.T.);
#1075=ORIENTED_EDGE('',*,*,#1064,.F.);
#1076=CARTESIAN_POINT('',(3.14233502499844E-13,-30.,20.));
#1077=DIRECTION('',(0.,0.,1.));
#1078=DIRECTION('',(0.,-1.,0.));
#1079=AXIS2_PLACEMENT_3D('',#1076,#1077,#1078);
#1080=CIRCLE('',#1079,10.);
#1081=CARTESIAN_POINT('',(9.82264602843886,-28.1249999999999,20.));
#1082=VERTEX_POINT('',#1081);
#1083=EDGE_CURVE('E615',#1082,#1057,#1080,.T.);
#1084=ORIENTED_EDGE('',*,*,#1083,.F.);
#1085=DIRECTION('',(0.,0.,1.));
#1086=VECTOR('',#1085,1.);
#1087=CARTESIAN_POINT('',(9.82264602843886,-28.1249999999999,20.));
#1088=LINE('',#1087,#1086);
#1089=EDGE_CURVE('E627',#1082,#113,#1088,.T.);
#1090=ORIENTED_EDGE('',*,*,#1089,.T.);
#1091=EDGE_LOOP('',(#1074,#1075,#1084,#1090));
#1092=FACE_BOUND('',#1091,.T.);
#1093=ADVANCED_FACE('F1097',(#1092),#1073,.F.);
#1094=CARTESIAN_POINT('',(9.82264602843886,-28.1249999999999,20.));
#1095=DIRECTION('',(0.982264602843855,0.18750000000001,0.));
#1096=DIRECTION('',(-0.18750000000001,0.982264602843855,0.));
#1097=AXIS2_PLACEMENT_3D('',#1094,#1095,#1096);
#1098=PLANE('',#1097);
#1099=ORIENTED_EDGE('',*,*,#120,.T.);
#1100=ORIENTED_EDGE('',*,*,#1089,.F.);
#1101=DIRECTION('',(-0.18750000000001,0.982264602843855,0.));
#1102=VECTOR('',#1101,1.);
#1103=CARTESIAN_POINT('',(9.82264602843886,-28.1249999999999,20.));
#1104=LINE('',#1103,#1102);
#1105=EDGE_CURVE('E612',#1024,#1082,#1104,.T.);
#1106=ORIENTED_EDGE('',*,*,#1105,.F.);
#1107=ORIENTED_EDGE('',*,*,#1025,.T.);
#1108=EDGE_LOOP('',(#1099,#1100,#1106,#1107));
#1109=FACE_BOUND('',#1108,.T.);
#1110=ADVANCED_FACE('F1105',(#1109),#1098,.F.);
#1111=CARTESIAN_POINT('',(1.1521895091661E-12,-110.,20.));
#1112=DIRECTION('',(0.,0.,1.));
#1113=DIRECTION('',(0.,-1.,0.));
#1114=AXIS2_PLACEMENT_3D('',#1111,#1112,#1113);
#1115=PLANE('',#1114);
#1116=ORIENTED_EDGE('',*,*,#1034,.T.);
#1117=ORIENTED_EDGE('',*,*,#1105,.T.);
#1118=ORIENTED_EDGE('',*,*,#1083,.T.);
#1119=ORIENTED_EDGE('',*,*,#1058,.T.);
#1120=EDGE_LOOP('',(#1116,#1117,#1118,#1119));
#1121=FACE_BOUND('',#1120,.T.);
#1122=ADVANCED_FACE('F1113',(#1121),#1115,.T.);
#1123=CARTESIAN_POINT('',(77.7817459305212,-77.7817459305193,20.));
#1124=DIRECTION('',(0.,0.,1.));
#1125=DIRECTION('',(1.,0.,0.));
#1126=AXIS2_PLACEMENT_3D('',#1123,#1124,#1125);
#1127=CYLINDRICAL_SURFACE('',#1126,25.);
#1128=ORIENTED_EDGE('',*,*,#61,.T.);
#1129=DIRECTION('',(0.,0.,1.));
#1130=VECTOR('',#1129,1.);
#1131=CARTESIAN_POINT('',(91.831331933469,-57.1030338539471,20.));
#1132=LINE('',#1131,#1130);
#1133=CARTESIAN_POINT('',(91.831331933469,-57.1030338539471,20.));
#1134=VERTEX_POINT('',#1133);
#1135=EDGE_CURVE('E571',#1134,#60,#1132,.T.);
#1136=ORIENTED_EDGE('',*,*,#1135,.F.);
#1137=CARTESIAN_POINT('',(77.7817459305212,-77.7817459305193,20.));
#1138=DIRECTION('',(0.,0.,1.));
#1139=DIRECTION('',(0.707106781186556,-0.707106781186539,0.));
#1140=AXIS2_PLACEMENT_3D('',#1137,#1138,#1139);
#1141=CIRCLE('',#1140,25.);
#1142=CARTESIAN_POINT('',(57.1030338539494,-91.8313319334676,20.));
#1143=VERTEX_POINT('',#1142);
#1144=EDGE_CURVE('E583',#1143,#1134,#1141,.T.);
#1145=ORIENTED_EDGE('',*,*,#1144,.F.);
#1146=DIRECTION('',(0.,0.,1.));
#1147=VECTOR('',#1146,1.);
#1148=CARTESIAN_POINT('',(57.1030338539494,-91.8313319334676,20.));
#1149=LINE('',#1148,#1147);
#1150=EDGE_CURVE('E595',#1143,#58,#1149,.T.);
#1151=ORIENTED_EDGE('',*,*,#1150,.T.);
#1152=EDGE_LOOP('',(#1128,#1136,#1145,#1151));
#1153=FACE_BOUND('',#1152,.T.);
#1154=ADVANCED_FACE('F1121',(#1153),#1127,.F.);
#1155=CARTESIAN_POINT('',(12.941718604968,-26.8330378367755,20.));
#1156=DIRECTION('',(-0.827148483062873,-0.561983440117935,0.));
#1157=DIRECTION('',(0.561983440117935,-0.827148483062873,0.));
#1158=AXIS2_PLACEMENT_3D('',#1155,#1156,#1157);
#1159=PLANE('',#1158);
#1160=ORIENTED_EDGE('',*,*,#69,.T.);
#1161=ORIENTED_EDGE('',*,*,#1150,.F.);
#1162=DIRECTION('',(0.561983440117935,-0.827148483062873,0.));
#1163=VECTOR('',#1162,1.);
#1164=CARTESIAN_POINT('',(12.941718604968,-26.8330378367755,20.));
#1165=LINE('',#1164,#1163);
#1166=CARTESIAN_POINT('',(12.941718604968,-26.8330378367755,20.));
#1167=VERTEX_POINT('',#1166);
#1168=EDGE_CURVE('E592',#1167,#1143,#1165,.T.);
#1169=ORIENTED_EDGE('',*,*,#1168,.F.);
#1170=DIRECTION('',(0.,0.,1.));
#1171=VECTOR('',#1170,1.);
#1172=CARTESIAN_POINT('',(12.941718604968,-26.8330378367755,20.));
#1173=LINE('',#1172,#1171);
#1174=EDGE_CURVE('E570',#1167,#68,#1173,.T.);
#1175=ORIENTED_EDGE('',*,*,#1174,.T.);
#1176=EDGE_LOOP('',(#1160,#1161,#1169,#1175));
#1177=FACE_BOUND('',#1176,.T.);
#1178=ADVANCED_FACE('F1129',(#1177),#1159,.F.);
#1179=CARTESIAN_POINT('',(21.2132034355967,-21.2132034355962,20.));
#1180=DIRECTION('',(0.,0.,1.));
#1181=DIRECTION('',(1.,0.,0.));
#1182=AXIS2_PLACEMENT_3D('',#1179,#1180,#1181);
#1183=CYLINDRICAL_SURFACE('',#1182,10.);
#1184=ORIENTED_EDGE('',*,*,#78,.T.);
#1185=ORIENTED_EDGE('',*,*,#1174,.F.);
#1186=CARTESIAN_POINT('',(21.2132034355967,-21.2132034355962,20.));
#1187=DIRECTION('',(0.,0.,1.));
#1188=DIRECTION('',(0.707106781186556,-0.707106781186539,0.));
#1189=AXIS2_PLACEMENT_3D('',#1186,#1187,#1188);
#1190=CIRCLE('',#1189,10.);
#1191=CARTESIAN_POINT('',(26.8330378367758,-12.9417186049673,20.));
#1192=VERTEX_POINT('',#1191);
#1193=EDGE_CURVE('E566',#1192,#1167,#1190,.T.);
#1194=ORIENTED_EDGE('',*,*,#1193,.F.);
#1195=DIRECTION('',(0.,0.,1.));
#1196=VECTOR('',#1195,1.);
#1197=CARTESIAN_POINT('',(26.8330378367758,-12.9417186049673,20.));
#1198=LINE('',#1197,#1196);
#1199=EDGE_CURVE('E559',#1192,#77,#1198,.T.);
#1200=ORIENTED_EDGE('',*,*,#1199,.T.);
#1201=EDGE_LOOP('',(#1184,#1185,#1194,#1200));
#1202=FACE_BOUND('',#1201,.T.);
#1203=ADVANCED_FACE('F561',(#1202),#1183,.F.);
#1204=CARTESIAN_POINT('',(26.8330378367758,-12.9417186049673,20.));
#1205=DIRECTION('',(0.561983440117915,0.827148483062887,0.));
#1206=DIRECTION('',(-0.827148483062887,0.561983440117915,0.));
#1207=AXIS2_PLACEMENT_3D('',#1204,#1205,#1206);
#1208=PLANE('',#1207);
#1209=ORIENTED_EDGE('',*,*,#84,.T.);
#1210=ORIENTED_EDGE('',*,*,#1199,.F.);
#1211=DIRECTION('',(-0.827148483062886,0.561983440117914,0.));
#1212=VECTOR('',#1211,1.);
#1213=CARTESIAN_POINT('',(26.8330378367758,-12.9417186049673,20.));
#1214=LINE('',#1213,#1212);
#1215=EDGE_CURVE('E589',#1134,#1192,#1214,.T.);
#1216=ORIENTED_EDGE('',*,*,#1215,.F.);
#1217=ORIENTED_EDGE('',*,*,#1135,.T.);
#1218=EDGE_LOOP('',(#1209,#1210,#1216,#1217));
#1219=FACE_BOUND('',#1218,.T.);
#1220=ADVANCED_FACE('F575',(#1219),#1208,.F.);
#1221=CARTESIAN_POINT('',(77.7817459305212,-77.7817459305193,20.));
#1222=DIRECTION('',(0.,0.,1.));
#1223=DIRECTION('',(0.707106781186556,-0.707106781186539,0.));
#1224=AXIS2_PLACEMENT_3D('',#1221,#1222,#1223);
#1225=PLANE('',#1224);
#1226=ORIENTED_EDGE('',*,*,#1144,.T.);
#1227=ORIENTED_EDGE('',*,*,#1215,.T.);
#1228=ORIENTED_EDGE('',*,*,#1193,.T.);
#1229=ORIENTED_EDGE('',*,*,#1168,.T.);
#1230=EDGE_LOOP('',(#1226,#1227,#1228,#1229));
#1231=FACE_BOUND('',#1230,.T.);
#1232=ADVANCED_FACE('F1149',(#1231),#1225,.T.);
#1233=CLOSED_SHELL('',(#46,#343,#352,#384,#408,#433,#450,#462,#494,#518,#543,#560,#572,#604,
#628,#653,#670,#682,#714,#738,#763,#780,#792,#824,#848,#873,#890,#902,#934,#958,#983,#1000,
#1012,#1044,#1068,#1093,#1110,#1122,#1154,#1178,#1203,#1220,#1232));
#1234=MANIFOLD_SOLID_BREP('B2',#1233);
#1235=ADVANCED_BREP_SHAPE_REPRESENTATION('',(#18,#1234),#14);
#1236=SHAPE_DEFINITION_REPRESENTATION(#9,#1235);
ENDSEC;
END-ISO-10303-21;
